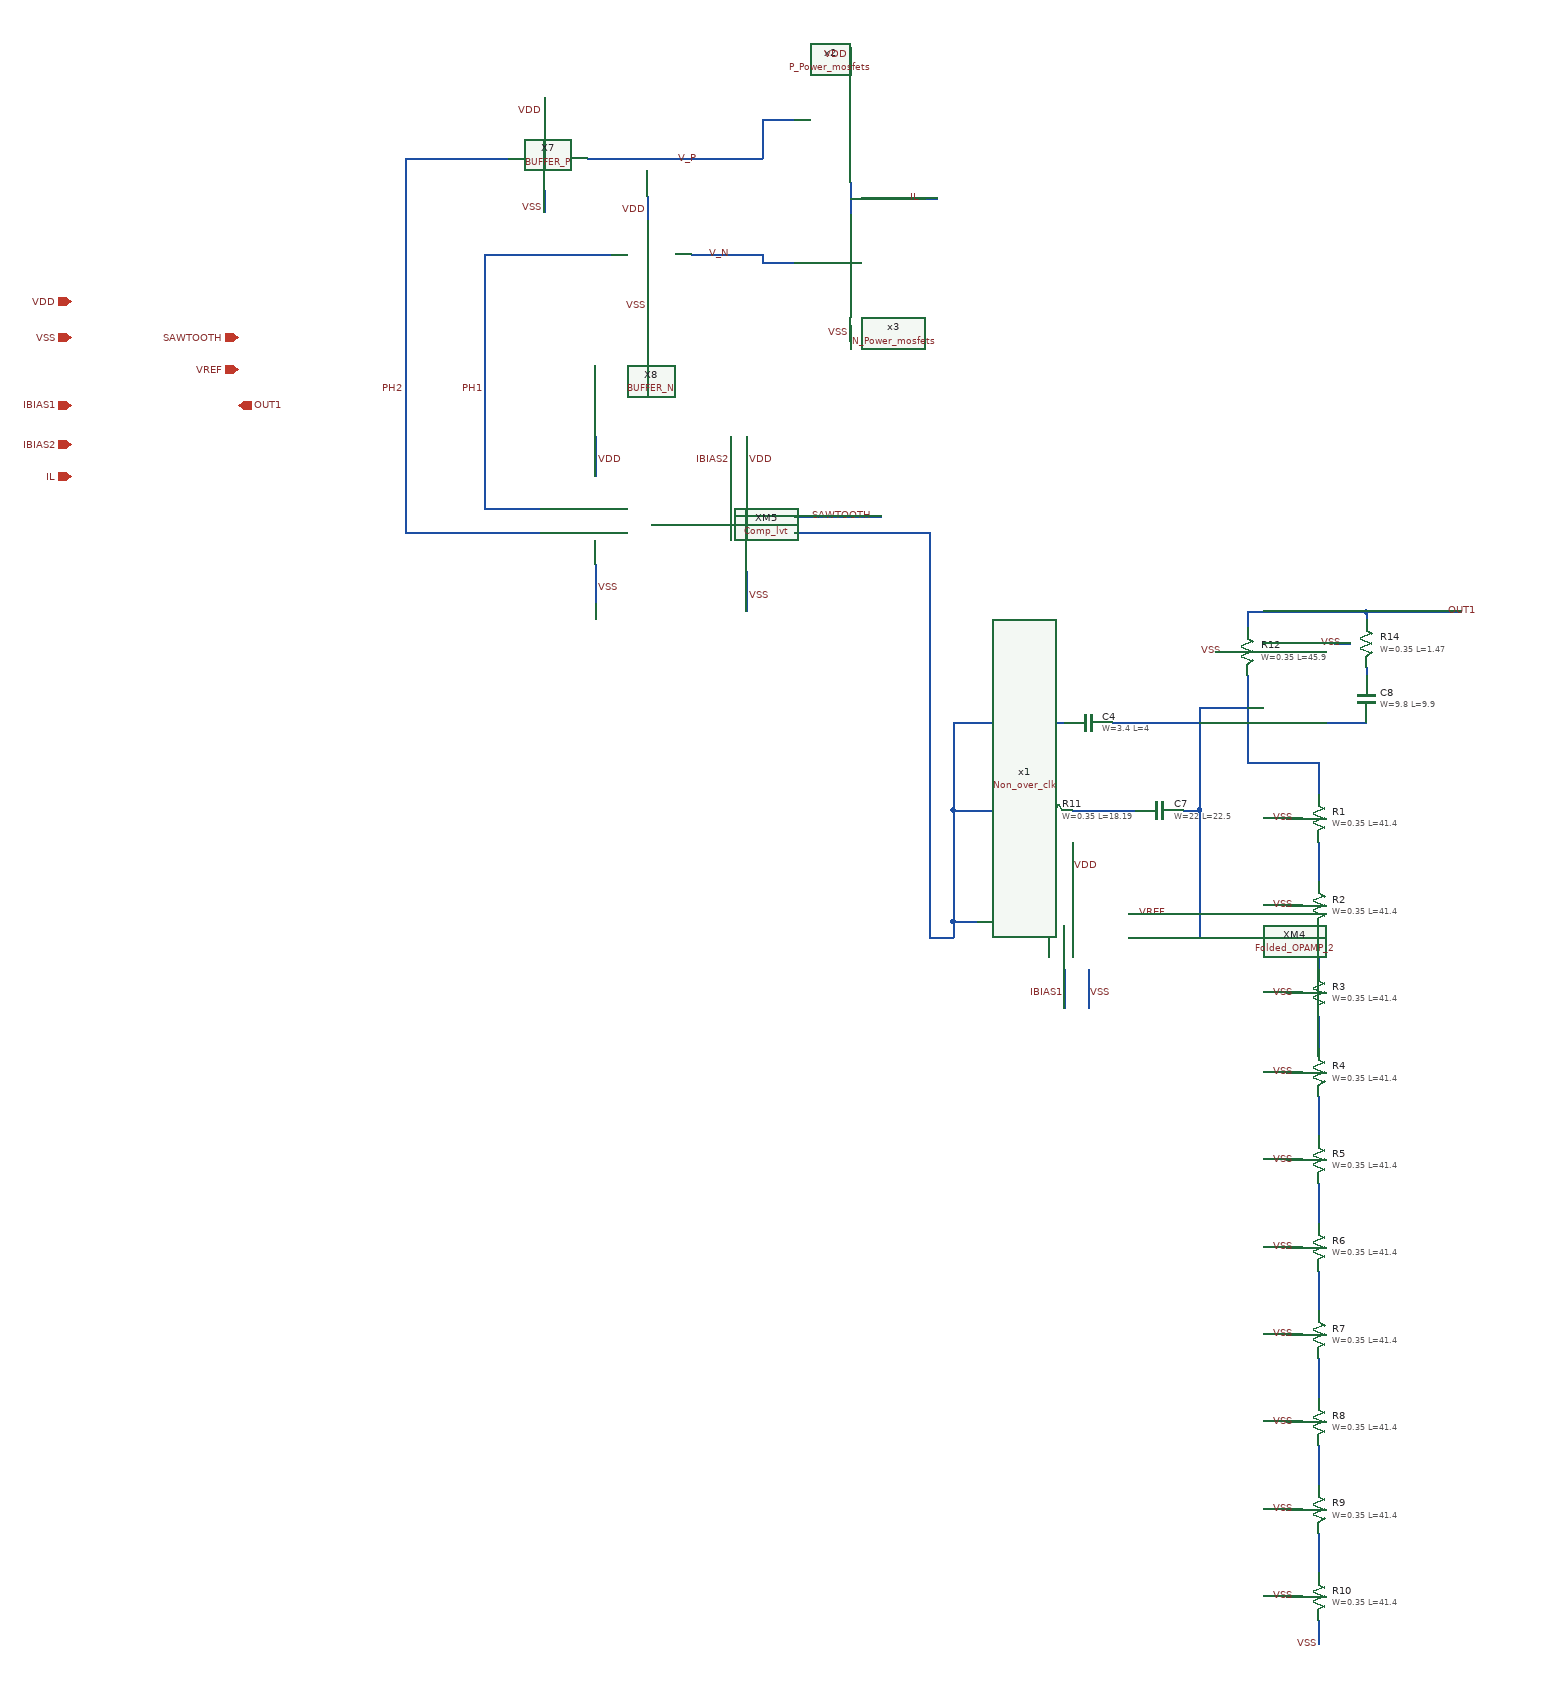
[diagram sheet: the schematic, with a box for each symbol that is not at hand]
v {xschem version=3.0.0 file_version=1.2 }
G {}
K {}
V {}
S {}
E {}
N 3550 -1770 3550 -1720 {
lab=VDD}
N 3570 -1610 3570 -1560 {
lab=VSS}
N 3540 -1610 3540 -1560 {
lab=IBIAS1}
N 3620 -1650 3670 -1650 {
lab=#net1}
N 3620 -1680 3670 -1680 {
lab=VREF}
N 3140 -2280 3140 -2230 {
lab=VDD}
N 3140 -2110 3140 -2060 {
lab=VSS}
N 3670 -1650 3700 -1650 {
lab=#net1}
N 3120 -2280 3120 -2230 {
lab=IBIAS2}
N 2940 -2630 3130 -2630 {
lab=V_P}
N 3770 -2060 3770 -2040 {
lab=OUT1}
N 3770 -1980 3770 -1930 {
lab=#net1}
N 3550 -1810 3630 -1810 {
lab=#net2}
N 3400 -1810 3490 -1810 {
lab=#net3}
N 3400 -1810 3400 -1670 {
lab=#net3}
N 3710 -1810 3710 -1680 {
lab=#net1}
N 3690 -1810 3710 -1810 {
lab=#net1}
N 3400 -1920 3540 -1920 {
lab=#net3}
N 3600 -1920 3710 -1920 {
lab=#net1}
N 3710 -1880 3710 -1810 {
lab=#net1}
N 3400 -1670 3430 -1670 {
lab=#net3}
N 3710 -1680 3710 -1650 {
lab=#net1}
N 3700 -1650 3710 -1650 {
lab=#net1}
N 3770 -2060 3920 -2060 {
lab=OUT1}
N 3920 -2060 3920 -2050 {
lab=OUT1}
N 3920 -1990 3920 -1980 {
lab=#net4}
N 3710 -1940 3710 -1880 {
lab=#net1}
N 3710 -1940 3770 -1940 {
lab=#net1}
N 3770 -1930 3770 -1900 {
lab=#net1}
N 3920 -2060 4040 -2060 {
lab=OUT1}
N 3200 -2160 3370 -2160 {
lab=#net3}
N 3400 -1670 3400 -1650 {
lab=#net3}
N 2950 -2280 2950 -2230 {
lab=VDD}
N 2950 -2120 2950 -2070 {
lab=VSS}
N 2710 -2630 2840 -2630 {
lab=PH2}
N 2710 -2630 2710 -2190 {
lab=PH2}
N 2885 -2590 2885 -2562.5 {
lab=VSS}
N 2885 -2707.5 2885 -2672.5 {
lab=VDD}
N 3070 -2510 3130 -2510 {
lab=V_N}
N 2810 -2510 2970 -2510 {
lab=PH1}
N 2810 -2510 2810 -2420 {
lab=PH1}
N 3015 -2470 3015 -2432.5 {
lab=VSS}
N 3015 -2582.5 3015 -2552.5 {
lab=VDD}
N 2810 -2190 2870 -2190 {
lab=PH1}
N 2810 -2420 2810 -2190 {
lab=PH1}
N 2710 -2160 2870 -2160 {
lab=PH2}
N 2710 -2190 2710 -2160 {
lab=PH2}
N 3400 -1920 3400 -1810 {
lab=#net3}
N 3770 -1920 3820 -1920 {
lab=#net1}
N 3820 -1920 3920 -1920 {
lab=#net1}
N 3570 -1610 3570 -1560 {
lab=VSS}
N 3200 -2180 3310 -2180 {
lab=SAWTOOTH}
N 3520 -1790 3520 -1770 {
lab=VSS}
N 3880 -2020 3900 -2020 {
lab=VSS}
N 3730 -2010 3750 -2010 {
lab=VSS}
N 2870 -2190 2880 -2190 {
lab=PH1}
N 2870 -2160 2880 -2160 {
lab=PH2}
N 3030 -2170 3070 -2170 {
lab=#net5}
N 3020 -2170 3030 -2170 {
lab=#net5}
N 3670 -1680 3680 -1680 {
lab=VREF}
N 3370 -2160 3370 -1650 {
lab=#net3}
N 3370 -1650 3400 -1650 {
lab=#net3}
N 3860 -1770 3860 -1720 {
lab=#net6}
N 3820 -1800 3840 -1800 {
lab=VSS}
N 3860 -1660 3860 -1610 {
lab=#net7}
N 3820 -1690 3840 -1690 {
lab=VSS}
N 3860 -1550 3860 -1500 {
lab=#net8}
N 3820 -1580 3840 -1580 {
lab=VSS}
N 3860 -1450 3860 -1400 {
lab=#net9}
N 3820 -1480 3840 -1480 {
lab=VSS}
N 3860 -1340 3860 -1290 {
lab=#net10}
N 3820 -1370 3840 -1370 {
lab=VSS}
N 3860 -1230 3860 -1180 {
lab=#net11}
N 3820 -1260 3840 -1260 {
lab=VSS}
N 3860 -1120 3860 -1070 {
lab=#net12}
N 3820 -1150 3840 -1150 {
lab=VSS}
N 3860 -1010 3860 -960 {
lab=#net13}
N 3820 -1040 3840 -1040 {
lab=VSS}
N 3860 -900 3860 -850 {
lab=#net14}
N 3820 -930 3840 -930 {
lab=VSS}
N 3820 -820 3840 -820 {
lab=VSS}
N 3770 -1900 3770 -1870 {
lab=#net1}
N 3770 -1870 3860 -1870 {
lab=#net1}
N 3860 -1870 3860 -1830 {
lab=#net1}
N 3860 -790 3860 -760 {
lab=VSS}
N 3130 -2630 3160 -2630 {
lab=V_P}
N 3160 -2680 3160 -2630 {
lab=V_P}
N 3160 -2680 3200 -2680 {
lab=V_P}
N 3130 -2510 3160 -2510 {
lab=V_N}
N 3160 -2510 3160 -2500 {
lab=V_N}
N 3160 -2500 3200 -2500 {
lab=V_N}
N 3270 -2600 3270 -2560 {
lab=IL}
N 3270 -2580 3380 -2580 {
lab=IL}
N 3270 -2420 3270 -2400 {
lab=VSS}
N 3270 -2770 3270 -2740 {
lab=VDD}
C {devices/iopin.sym} 2290 -2450 0 0 {name=p3 lab=VDD}
C {devices/iopin.sym} 2290 -2405 0 0 {name=p4 lab=VSS}
C {devices/iopin.sym} 2290 -2320 0 0 {name=p5 lab=IBIAS1}
C {devices/iopin.sym} 2500 -2405 0 0 {name=p6 lab=SAWTOOTH}
C {devices/iopin.sym} 2500 -2365 0 0 {name=p7 lab=VREF}
C {devices/iopin.sym} 2290 -2270 0 0 {name=p8 lab=IBIAS2}
C {devices/iopin.sym} 2500 -2320 0 1 {name=p11 lab=OUT1}
C {devices/lab_wire.sym} 3550 -1740 0 1 {name=l101 sig_type=std_logic lab=VDD}
C {devices/lab_wire.sym} 3570 -1580 0 1 {name=l104 sig_type=std_logic lab=VSS}
C {devices/lab_wire.sym} 3540 -1580 0 0 {name=l105 sig_type=std_logic lab=IBIAS1}
C {devices/lab_wire.sym} 3140 -2250 0 1 {name=l106 sig_type=std_logic lab=VDD}
C {devices/lab_wire.sym} 3140 -2080 0 1 {name=l107 sig_type=std_logic lab=VSS}
C {devices/lab_wire.sym} 3120 -2250 0 0 {name=l110 sig_type=std_logic lab=IBIAS2}
C {devices/lab_wire.sym} 3670 -1680 0 0 {name=l115 sig_type=std_logic lab=VREF}
C {devices/lab_wire.sym} 3300 -2180 0 0 {name=l116 sig_type=std_logic lab=SAWTOOTH}
C {devices/lab_wire.sym} 2950 -2250 0 1 {name=l121 sig_type=std_logic lab=VDD}
C {devices/lab_wire.sym} 2950 -2090 0 1 {name=l122 sig_type=std_logic lab=VSS}
C {DC_DC_Converter/BUFFER/BUFFER_PMOS/BUFFER_P.sym} 2820 -2580 0 0 {name=X7}
C {devices/lab_wire.sym} 2885 -2690 0 0 {name=l123 sig_type=std_logic lab=VDD}
C {devices/lab_wire.sym} 2885 -2567.5 0 0 {name=l124 sig_type=std_logic lab=VSS}
C {devices/lab_wire.sym} 3015 -2445 0 0 {name=l125 sig_type=std_logic lab=VSS}
C {devices/lab_wire.sym} 3015 -2565 0 0 {name=l126 sig_type=std_logic lab=VDD}
C {devices/lab_wire.sym} 3080 -2630 0 0 {name=l127 sig_type=std_logic lab=V_P}
C {sky130_fd_pr/cap_mim_m3_1.sym} 3570 -1920 3 0 {name=C4 model=cap_mim_m3_1 W=3.4 L=4 MF=1 spiceprefix=X}
C {sky130_fd_pr/cap_mim_m3_1.sym} 3660 -1810 3 0 {name=C7 model=cap_mim_m3_1 W=22 L=22.5 MF=1 spiceprefix=X}
C {sky130_fd_pr/cap_mim_m3_1.sym} 3920 -1950 0 0 {name=C8 model=cap_mim_m3_1 W=9.8 L=9.9 MF=1 spiceprefix=X}
C {DC_DC_Converter/Comparator/Comp_lvt.sym} 3220 -2100 0 1 {name=XM5}
C {devices/lab_wire.sym} 3520 -1780 3 0 {name=l132 sig_type=std_logic lab=VSS}
C {devices/lab_wire.sym} 3890 -2020 0 0 {name=l133 sig_type=std_logic lab=VSS}
C {devices/lab_wire.sym} 3740 -2010 0 0 {name=l134 sig_type=std_logic lab=VSS}
C {DC_DC_Converter/BUFFER/BUFFER_NMOS/BUFFER_N.sym} 2880 -2430 0 0 {name=X8}
C {sky130_fd_pr/res_xhigh_po_0p35.sym} 3520 -1810 3 0 {name=R11
W=0.35
L=18.19
model=res_xhigh_po_0p35
spiceprefix=X
mult=1}
C {sky130_fd_pr/res_xhigh_po_0p35.sym} 3770 -2010 0 0 {name=R12
W=0.35
L=45.9
model=res_xhigh_po_0p35
spiceprefix=X
mult=1}
C {devices/lab_wire.sym} 2810 -2340 0 0 {name=l137 sig_type=std_logic lab=PH1}
C {devices/lab_wire.sym} 2710 -2340 0 0 {name=l138 sig_type=std_logic lab=PH2}
C {sky130_fd_pr/res_xhigh_po_0p35.sym} 3920 -2020 0 0 {name=R14
W=0.35
L=1.47
model=res_xhigh_po_0p35
spiceprefix=X
mult=1}
C {DC_DC_Converter/Folded_OPAMP/Folded_OPAMP_2.sym} 3770 -1500 0 1 {name=XM4}
C {devices/lab_wire.sym} 4020 -2060 0 1 {name=l7 sig_type=std_logic lab=OUT1}
C {devices/lab_wire.sym} 3120 -2510 0 0 {name=l1 sig_type=std_logic lab=V_N}
C {devices/lab_wire.sym} 3830 -1800 0 0 {name=l2 sig_type=std_logic lab=VSS}
C {sky130_fd_pr/res_xhigh_po_0p35.sym} 3860 -1800 0 0 {name=R1
W=0.35
L=41.4
model=res_xhigh_po_0p35
spiceprefix=X
mult=1}
C {devices/lab_wire.sym} 3830 -1690 0 0 {name=l3 sig_type=std_logic lab=VSS}
C {sky130_fd_pr/res_xhigh_po_0p35.sym} 3860 -1690 0 0 {name=R2
W=0.35
L=41.4
model=res_xhigh_po_0p35
spiceprefix=X
mult=1}
C {devices/lab_wire.sym} 3830 -1580 0 0 {name=l5 sig_type=std_logic lab=VSS}
C {sky130_fd_pr/res_xhigh_po_0p35.sym} 3860 -1580 0 0 {name=R3
W=0.35
L=41.4
model=res_xhigh_po_0p35
spiceprefix=X
mult=1}
C {devices/lab_wire.sym} 3830 -1480 0 0 {name=l8 sig_type=std_logic lab=VSS}
C {sky130_fd_pr/res_xhigh_po_0p35.sym} 3860 -1480 0 0 {name=R4
W=0.35
L=41.4
model=res_xhigh_po_0p35
spiceprefix=X
mult=1}
C {devices/lab_wire.sym} 3830 -1370 0 0 {name=l10 sig_type=std_logic lab=VSS}
C {sky130_fd_pr/res_xhigh_po_0p35.sym} 3860 -1370 0 0 {name=R5
W=0.35
L=41.4
model=res_xhigh_po_0p35
spiceprefix=X
mult=1}
C {devices/lab_wire.sym} 3830 -1260 0 0 {name=l12 sig_type=std_logic lab=VSS}
C {sky130_fd_pr/res_xhigh_po_0p35.sym} 3860 -1260 0 0 {name=R6
W=0.35
L=41.4
model=res_xhigh_po_0p35
spiceprefix=X
mult=1}
C {devices/lab_wire.sym} 3830 -1150 0 0 {name=l14 sig_type=std_logic lab=VSS}
C {sky130_fd_pr/res_xhigh_po_0p35.sym} 3860 -1150 0 0 {name=R7
W=0.35
L=41.4
model=res_xhigh_po_0p35
spiceprefix=X
mult=1}
C {devices/lab_wire.sym} 3830 -1040 0 0 {name=l16 sig_type=std_logic lab=VSS}
C {sky130_fd_pr/res_xhigh_po_0p35.sym} 3860 -1040 0 0 {name=R8
W=0.35
L=41.4
model=res_xhigh_po_0p35
spiceprefix=X
mult=1}
C {devices/lab_wire.sym} 3830 -930 0 0 {name=l18 sig_type=std_logic lab=VSS}
C {sky130_fd_pr/res_xhigh_po_0p35.sym} 3860 -930 0 0 {name=R9
W=0.35
L=41.4
model=res_xhigh_po_0p35
spiceprefix=X
mult=1}
C {devices/lab_wire.sym} 3860 -760 0 0 {name=l19 sig_type=std_logic lab=VSS}
C {devices/lab_wire.sym} 3830 -820 0 0 {name=l20 sig_type=std_logic lab=VSS}
C {sky130_fd_pr/res_xhigh_po_0p35.sym} 3860 -820 0 0 {name=R10
W=0.35
L=41.4
model=res_xhigh_po_0p35
spiceprefix=X
mult=1}
C {DC_DC_Converter/Non_Overlap_Clk/Non_over_clk.sym} 3150 -1910 0 1 {name=x1}
C {DC_DC_Converter/Power_Mosfet/P_Power_mosfets.sym} 3280 -2680 0 0 {name=x2}
C {DC_DC_Converter/Power_Mosfet/N_Power_mosfets.sym} 3280 -2500 0 0 {name=x3}
C {devices/lab_wire.sym} 3270 -2760 0 0 {name=l4 sig_type=std_logic lab=VDD}
C {devices/lab_wire.sym} 3270 -2410 0 0 {name=l6 sig_type=std_logic lab=VSS}
C {devices/lab_wire.sym} 3360 -2580 0 0 {name=l9 sig_type=std_logic lab=IL}
C {devices/iopin.sym} 2290 -2230 0 0 {name=p1 lab=IL}
